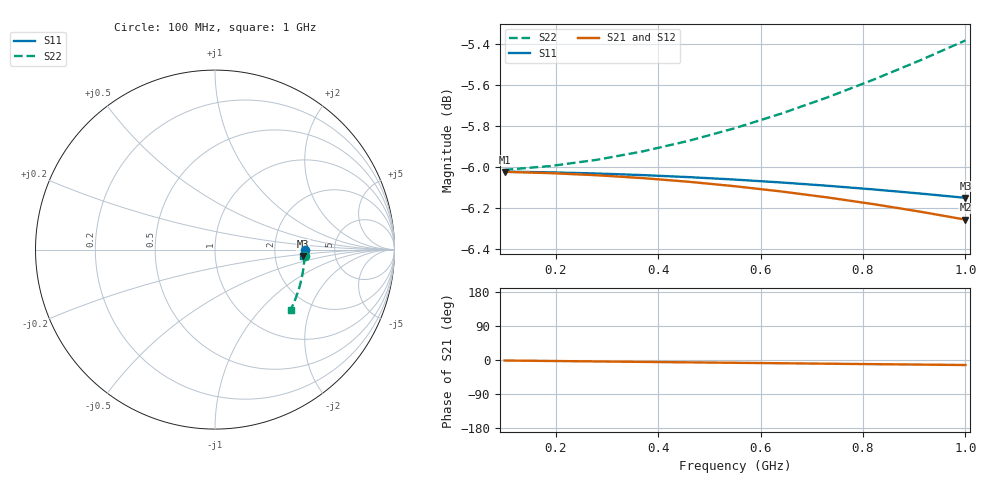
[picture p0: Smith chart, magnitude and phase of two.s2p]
# Hz S RI R 50
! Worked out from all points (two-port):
!   11 points, 100 MHz to 1 GHz, reference 50 ohm
!   highest |S21| = -6.02 dB at 100 MHz (marker M1); lowest = -6.3 dB at 1 GHz (marker M2)
!   |S21| within 3 dB of the highest: start of sweep to end of sweep
!   lowest |S11| = -6.1 dB at 1 GHz (marker M3), VSWR 2.94, Z = 146 - j14.3 ohm
!   |S11| at or under -10 dB: nowhere
!   |S22| runs from -6.0 to -5.4 dB; largest |S21 - S12| = 0
1e8  0.4999 -0.00392  0.4997 -0.0118  0.4997 -0.0118  0.4992 -0.0353
1.9e8  0.4997 -0.00745  0.499 -0.0223  0.499 -0.0223  0.497 -0.067
2.8e8  0.4993 -0.0109  0.4978 -0.0328  0.4978 -0.0328  0.4935 -0.0985
3.7e8  0.4987 -0.0144  0.4962 -0.0433  0.4962 -0.0433  0.4887 -0.1298
4.6e8  0.4981 -0.0179  0.4942 -0.0536  0.4942 -0.0536  0.4826 -0.1607
5.5e8  0.4972 -0.0212  0.4917 -0.0637  0.4917 -0.0637  0.4752 -0.1912
6.4e8  0.4963 -0.0246  0.4889 -0.0737  0.4889 -0.0737  0.4666 -0.2212
7.3e8  0.4952 -0.0278  0.4856 -0.0835  0.4856 -0.0835  0.4569 -0.2506
8.2e8  0.494 -0.031  0.482 -0.0931  0.482 -0.0931  0.446 -0.2794
9.1e8  0.4927 -0.0342  0.478 -0.1025  0.478 -0.1025  0.4341 -0.3075
1e9  0.4912 -0.0372  0.4737 -0.1116  0.4737 -0.1116  0.4211 -0.3348
